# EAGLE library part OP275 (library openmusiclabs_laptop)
Dual Bipolar/JFET, Audio Operational Amplifier Analog Devices www.openmusiclabs.com 2010

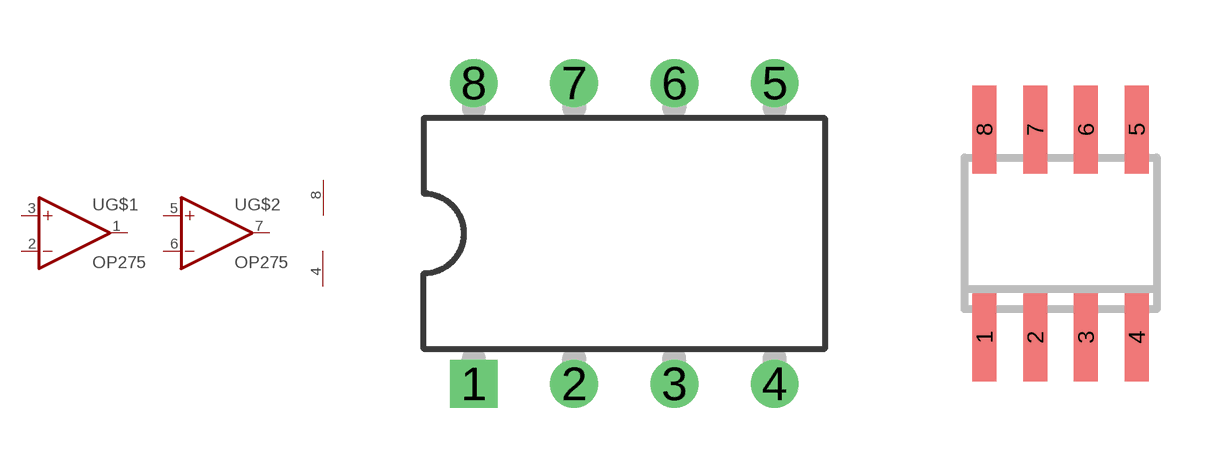
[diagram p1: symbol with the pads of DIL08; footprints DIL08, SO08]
Designator prefix -; gates G$1=OPAMP G$2=OPAMP G$3=PWR+-

## OP275DIP  [DIL08]
1  G$1:OUT  out
2  G$1:-IN  in
3  G$1:+IN  in
4  G$3:V-  pwr
5  G$2:+IN  in
6  G$2:-IN  in
7  G$2:OUT  out
8  G$3:V+  pwr

## OP275SOIC  [SO08]
Pads as for DIL08

## Footprint DIL08 (pad centres in mm)
Dual In Line Package
drill 0.7 square: 1 -3.81,-3.81
drill 0.7 round: 2 -1.27,-3.81; 3 1.27,-3.81; 4 3.81,-3.81; 5 3.81,3.81; 6 1.27,3.81; 7 -1.27,3.81; 8 -3.81,3.81

## Footprint SO08 (pad centres in mm)
Small Outline Package 8 NS Package M08A
smd 0.6 x 2.2: 1 -1.905,-2.6; 2 -0.635,-2.6; 3 0.635,-2.6; 4 1.905,-2.6; 5 1.905,2.6; 6 0.635,2.6; 7 -0.635,2.6; 8 -1.905,2.6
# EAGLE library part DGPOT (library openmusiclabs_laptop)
Dual Ganged Potentiometer two voltage dividers controlled by a single knob the arrow indicates the clockwise motion of th wiper (lug 2) fully counter clockwise there is no resistance between lugs 1 and 2 fully clockwise the resistance between lugs 1 and 2 is the value of the pot Source: taken from library "gm-pots.lbr" http://gaussmarkov.net/wordpress/tools/software/eagle/eagle-2-libraries/ openmusiclabs.com 2010

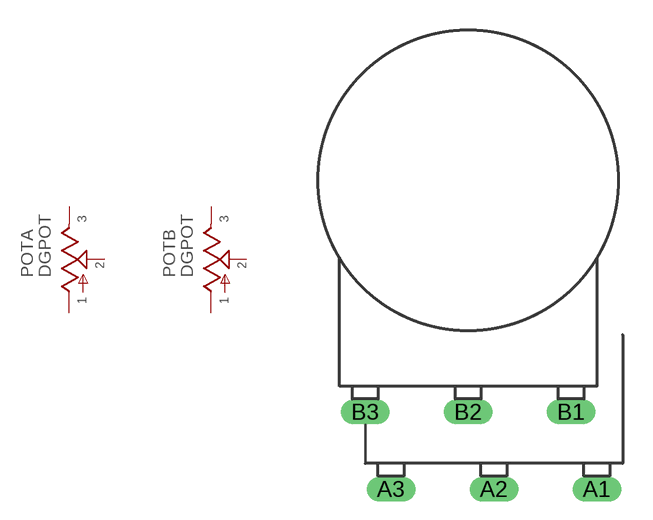
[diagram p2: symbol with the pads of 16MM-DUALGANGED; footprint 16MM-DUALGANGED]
Designator prefix POT; gates A=POT B=POT

## DGPOT  [16MM-DUALGANGED]
A1  A:1  pas
A2  A:2  pas
A3  A:3  pas
B1  B:1  pas
B2  B:2  pas
B3  B:3  pas

## Footprint 16MM-DUALGANGED (pad centres in mm)
drill 0.7 long: A1 6.35,-11.43; A2 1.27,-11.43; A3 -3.81,-11.43; B1 5.08,-7.62; B2 0,-7.62; B3 -5.08,-7.62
